VERSION 5.7 ;
  NOWIREEXTENSIONATPIN ON ;
  DIVIDERCHAR "/" ;
  BUSBITCHARS "[]" ;
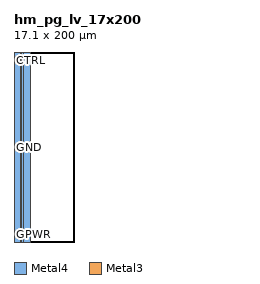
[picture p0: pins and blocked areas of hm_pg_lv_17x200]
MACRO hm_pg_lv_17x200
  CLASS BLOCK ;
  FOREIGN hm_pg_lv_17x200 ;
  ORIGIN 0.100 158.610 ;
  SIZE 17.100 BY 200.000 ;
  PIN VPWR
    DIRECTION INOUT ;
    USE POWER ;
    PORT
      LAYER Metal4 ;
        RECT 0.000 -158.610 7.000 41.390 ;
    END
  END VPWR
  PIN GND
    DIRECTION INOUT ;
    USE GROUND ;
    PORT
      LAYER Metal4 ;
        RECT 7.300 -158.610 9.700 41.390 ;
    END
  END GND
  PIN GPWR
    DIRECTION INOUT ;
    USE POWER ;
    PORT
      LAYER Metal4 ;
        RECT 10.000 -158.610 17.000 41.390 ;
    END
  END GPWR
  PIN CTRL
    DIRECTION INPUT ;
    USE SIGNAL ;
    ANTENNAGATEAREA 1.560000 ;
    PORT
      LAYER Metal3 ;
        RECT 8.235 40.890 10.635 41.390 ;
    END
  END CTRL
  OBS
      LAYER GatPoly ;
        RECT 0.030 -158.370 16.760 40.530 ;
      LAYER Metal1 ;
        RECT 0.030 -158.370 16.760 40.530 ;
      LAYER Metal2 ;
        RECT 0.000 -157.440 16.220 41.390 ;
      LAYER Metal3 ;
        RECT 0.000 -158.610 17.000 40.360 ;
  END
END hm_pg_lv_17x200
END LIBRARY

